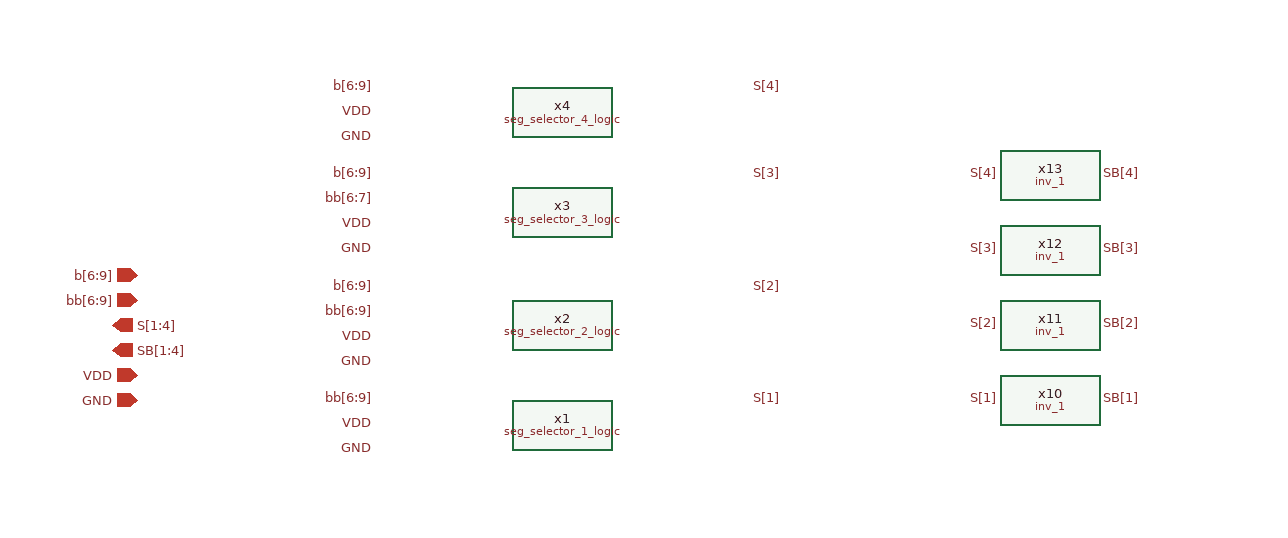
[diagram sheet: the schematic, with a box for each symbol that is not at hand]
v {xschem version=3.4.8RC file_version=1.2}
G {}
K {}
V {}
S {}
E {}
C {devices/title.sym} 160 -40 0 0 {name=l1 author="Yohanes Stefanus"}
C {devices/ipin.sym} 70 -270 0 0 {name=p39 lab=b[6:9]}
C {devices/opin.sym} 50 -230 0 0 {name=p41 lab=S[1:4]}
C {devices/ipin.sym} 70 -170 0 0 {name=p43 lab=GND}
C {devices/lab_pin.sym} 260 -260 0 0 {name=p46 sig_type=std_logic lab=b[6:9]}
C {devices/lab_pin.sym} 260 -170 0 0 {name=p47 sig_type=std_logic lab=bb[6:9]}
C {devices/lab_pin.sym} 560 -170 0 1 {name=p49 sig_type=std_logic lab=S[1]}
C {devices/lab_pin.sym} 260 -200 0 0 {name=p51 sig_type=std_logic lab=GND}
C {devices/lab_pin.sym} 260 -130 0 0 {name=p53 sig_type=std_logic lab=GND}
C {devices/lab_pin.sym} 260 -220 0 0 {name=p50 sig_type=std_logic lab=VDD}
C {devices/lab_pin.sym} 260 -150 0 0 {name=p52 sig_type=std_logic lab=VDD}
C {devices/ipin.sym} 70 -190 0 0 {name=p62 lab=VDD}
C {devices/lab_pin.sym} 260 -310 0 0 {name=p3 sig_type=std_logic lab=VDD}
C {devices/lab_pin.sym} 260 -290 0 0 {name=p4 sig_type=std_logic lab=GND}
C {devices/lab_pin.sym} 260 -400 0 0 {name=p5 sig_type=std_logic lab=VDD}
C {devices/lab_pin.sym} 260 -380 0 0 {name=p6 sig_type=std_logic lab=GND}
C {seg_selector_1_logic.sym} 410 -150 0 0 {name=x1}
C {seg_selector_2_logic.sym} 410 -230 0 0 {name=x2}
C {devices/lab_pin.sym} 260 -240 0 0 {name=p1 sig_type=std_logic lab=bb[6:9]}
C {seg_selector_3_logic.sym} 410 -320 0 0 {name=x3}
C {devices/lab_pin.sym} 260 -420 0 0 {name=p2 sig_type=std_logic lab=b[6:9]}
C {devices/lab_pin.sym} 260 -330 0 0 {name=p7 sig_type=std_logic lab=bb[6:7]}
C {seg_selector_4_logic.sym} 410 -400 0 0 {name=x4}
C {devices/lab_pin.sym} 260 -350 0 0 {name=p8 sig_type=std_logic lab=b[6:9]}
C {devices/ipin.sym} 70 -250 0 0 {name=p9 lab=bb[6:9]}
C {devices/lab_pin.sym} 560 -260 0 1 {name=p10 sig_type=std_logic lab=S[2]}
C {devices/lab_pin.sym} 560 -350 0 1 {name=p11 sig_type=std_logic lab=S[3]}
C {devices/lab_pin.sym} 560 -420 0 1 {name=p12 sig_type=std_logic lab=S[4]}
C {sky130_stdcells/inv_1.sym} 800 -170 0 0 {name=x10 VGND=GND VNB=GND VPB=VDD VPWR=VDD prefix=sky130_fd_sc_hd__ }
C {sky130_stdcells/inv_1.sym} 800 -230 0 0 {name=x11 VGND=GND VNB=GND VPB=VDD VPWR=VDD prefix=sky130_fd_sc_hd__ }
C {sky130_stdcells/inv_1.sym} 800 -290 0 0 {name=x12 VGND=GND VNB=GND VPB=VDD VPWR=VDD prefix=sky130_fd_sc_hd__ }
C {sky130_stdcells/inv_1.sym} 800 -350 0 0 {name=x13 VGND=GND VNB=GND VPB=VDD VPWR=VDD prefix=sky130_fd_sc_hd__ }
C {devices/lab_pin.sym} 760 -170 0 0 {name=p33 sig_type=std_logic lab=S[1]}
C {devices/lab_pin.sym} 760 -230 0 0 {name=p34 sig_type=std_logic lab=S[2]}
C {devices/lab_pin.sym} 760 -290 0 0 {name=p35 sig_type=std_logic lab=S[3]}
C {devices/lab_pin.sym} 760 -350 0 0 {name=p36 sig_type=std_logic lab=S[4]}
C {devices/lab_pin.sym} 840 -350 0 1 {name=p37 sig_type=std_logic lab=SB[4]}
C {devices/lab_pin.sym} 840 -290 0 1 {name=p38 sig_type=std_logic lab=SB[3]}
C {devices/lab_pin.sym} 840 -230 0 1 {name=p13 sig_type=std_logic lab=SB[2]}
C {devices/lab_pin.sym} 840 -170 0 1 {name=p40 sig_type=std_logic lab=SB[1]}
C {devices/opin.sym} 50 -210 0 0 {name=p14 lab=SB[1:4]}
